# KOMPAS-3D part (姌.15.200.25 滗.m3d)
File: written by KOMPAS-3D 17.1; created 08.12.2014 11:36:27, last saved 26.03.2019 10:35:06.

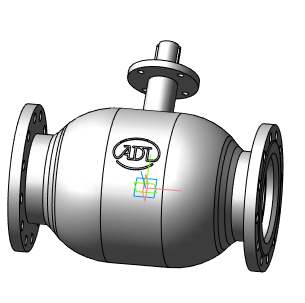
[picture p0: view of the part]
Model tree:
1. Операция без истории:4  (labels: Сталь 20  ГОСТ 1050-88)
